One B-rep face of a CAD part: STEP entity #753.
In plain terms, the planar face has unit normal (1, 0, 0).
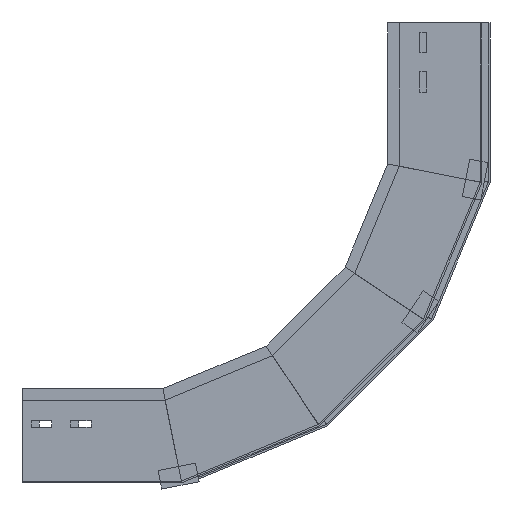
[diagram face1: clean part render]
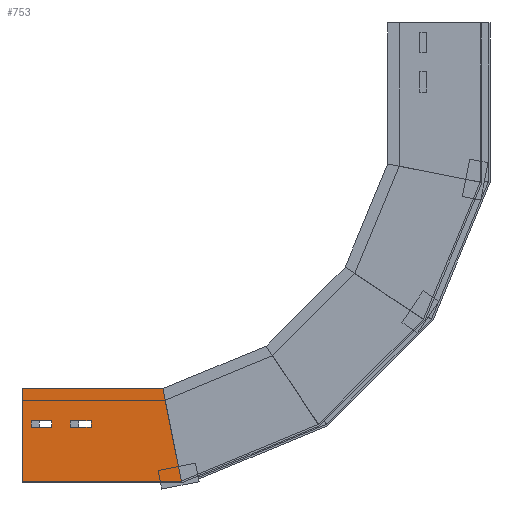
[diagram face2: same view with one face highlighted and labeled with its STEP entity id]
Its self-contained STEP definition (entity closure, numbers rounded to 3 decimals):
#6 = EDGE_LOOP ( 'NONE', ( #762, #1811, #141, #299 ) ) ;
#30 = EDGE_CURVE ( 'NONE', #997, #331, #841, .T. ) ;
#33 = ORIENTED_EDGE ( 'NONE', *, *, #143, .T. ) ;
#48 = LINE ( 'NONE', #607, #615 ) ;
#61 = LINE ( 'NONE', #1684, #849 ) ;
#67 = LINE ( 'NONE', #475, #1710 ) ;
#102 = ORIENTED_EDGE ( 'NONE', *, *, #1263, .T. ) ;
#112 = CARTESIAN_POINT ( 'NONE',  ( 0., 66., -73.505 ) ) ;
#126 = VECTOR ( 'NONE', #1705, 1000. ) ;
#138 = EDGE_LOOP ( 'NONE', ( #947, #1487, #102, #853 ) ) ;
#141 = ORIENTED_EDGE ( 'NONE', *, *, #1051, .T. ) ;
#143 = EDGE_CURVE ( 'NONE', #388, #1275, #904, .T. ) ;
#145 = CARTESIAN_POINT ( 'NONE',  ( 0., 100., 0. ) ) ;
#156 = VERTEX_POINT ( 'NONE', #768 ) ;
#172 = DIRECTION ( 'NONE',  ( 0., 1., 0. ) ) ;
#203 = EDGE_CURVE ( 'NONE', #1849, #1250, #673, .T. ) ;
#275 = FACE_BOUND ( 'NONE', #6, .T. ) ;
#290 = CARTESIAN_POINT ( 'NONE',  ( 0., 0., 0. ) ) ;
#298 = LINE ( 'NONE', #458, #333 ) ;
#299 = ORIENTED_EDGE ( 'NONE', *, *, #203, .T. ) ;
#312 = EDGE_CURVE ( 'NONE', #1637, #825, #48, .T. ) ;
#327 = CARTESIAN_POINT ( 'NONE',  ( 0., 59., -9.835 ) ) ;
#331 = VERTEX_POINT ( 'NONE', #828 ) ;
#333 = VECTOR ( 'NONE', #1773, 1000. ) ;
#344 = CARTESIAN_POINT ( 'NONE',  ( 0., 0., 0. ) ) ;
#382 = CARTESIAN_POINT ( 'NONE',  ( 0., 66., -31.835 ) ) ;
#388 = VERTEX_POINT ( 'NONE', #990 ) ;
#418 = EDGE_CURVE ( 'NONE', #1558, #985, #67, .T. ) ;
#425 = VECTOR ( 'NONE', #1557, 1000. ) ;
#450 = PLANE ( 'NONE',  #733 ) ;
#453 = DIRECTION ( 'NONE',  ( 0., 0., -1. ) ) ;
#458 = CARTESIAN_POINT ( 'NONE',  ( 0., 66., -9.835 ) ) ;
#467 = CARTESIAN_POINT ( 'NONE',  ( 0., 66., -51.505 ) ) ;
#475 = CARTESIAN_POINT ( 'NONE',  ( 0., 0., 0. ) ) ;
#557 = CARTESIAN_POINT ( 'NONE',  ( 0., 66., -31.835 ) ) ;
#590 = EDGE_LOOP ( 'NONE', ( #625, #1591, #864, #33 ) ) ;
#607 = CARTESIAN_POINT ( 'NONE',  ( 0., 66., -9.835 ) ) ;
#608 = EDGE_CURVE ( 'NONE', #825, #388, #1416, .T. ) ;
#609 = CARTESIAN_POINT ( 'NONE',  ( 0., 100., 0. ) ) ;
#612 = DIRECTION ( 'NONE',  ( 0., 0., -1. ) ) ;
#615 = VECTOR ( 'NONE', #453, 1000. ) ;
#625 = ORIENTED_EDGE ( 'NONE', *, *, #1156, .T. ) ;
#629 = LINE ( 'NONE', #1791, #1453 ) ;
#647 = DIRECTION ( 'NONE',  ( 0., 0., -1. ) ) ;
#651 = DIRECTION ( 'NONE',  ( 0., 1., 0. ) ) ;
#673 = LINE ( 'NONE', #1799, #1180 ) ;
#733 = AXIS2_PLACEMENT_3D ( 'NONE', #290, #854, #1869 ) ;
#753 = ADVANCED_FACE ( 'NONE', ( #275, #1876, #1459 ), #450, .F. ) ;
#754 = DIRECTION ( 'NONE',  ( 0., 0., -1. ) ) ;
#759 = VECTOR ( 'NONE', #754, 1000. ) ;
#762 = ORIENTED_EDGE ( 'NONE', *, *, #1502, .T. ) ;
#768 = CARTESIAN_POINT ( 'NONE',  ( 0., 66., -51.505 ) ) ;
#800 = CARTESIAN_POINT ( 'NONE',  ( 0., 66., -73.505 ) ) ;
#825 = VERTEX_POINT ( 'NONE', #557 ) ;
#828 = CARTESIAN_POINT ( 'NONE',  ( 0., 0., -169.6 ) ) ;
#841 = LINE ( 'NONE', #1286, #1485 ) ;
#849 = VECTOR ( 'NONE', #647, 1000. ) ;
#853 = ORIENTED_EDGE ( 'NONE', *, *, #30, .F. ) ;
#854 = DIRECTION ( 'NONE',  ( -1., 0., 0. ) ) ;
#864 = ORIENTED_EDGE ( 'NONE', *, *, #608, .T. ) ;
#904 = LINE ( 'NONE', #327, #1615 ) ;
#946 = CARTESIAN_POINT ( 'NONE',  ( 0., 59., -9.835 ) ) ;
#947 = ORIENTED_EDGE ( 'NONE', *, *, #1493, .F. ) ;
#985 = VERTEX_POINT ( 'NONE', #145 ) ;
#990 = CARTESIAN_POINT ( 'NONE',  ( 0., 59., -31.835 ) ) ;
#997 = VERTEX_POINT ( 'NONE', #1128 ) ;
#998 = VECTOR ( 'NONE', #172, 1000. ) ;
#1051 = EDGE_CURVE ( 'NONE', #1704, #1849, #1572, .T. ) ;
#1128 = CARTESIAN_POINT ( 'NONE',  ( 0., 100., -149.709 ) ) ;
#1156 = EDGE_CURVE ( 'NONE', #1275, #1637, #298, .T. ) ;
#1159 = DIRECTION ( 'NONE',  ( 0., 0., 1. ) ) ;
#1180 = VECTOR ( 'NONE', #1653, 1000. ) ;
#1237 = EDGE_CURVE ( 'NONE', #156, #1704, #629, .T. ) ;
#1250 = VERTEX_POINT ( 'NONE', #1359 ) ;
#1263 = EDGE_CURVE ( 'NONE', #1558, #331, #61, .T. ) ;
#1275 = VERTEX_POINT ( 'NONE', #946 ) ;
#1286 = CARTESIAN_POINT ( 'NONE',  ( 0., 32.452, -163.145 ) ) ;
#1359 = CARTESIAN_POINT ( 'NONE',  ( 0., 59., -51.505 ) ) ;
#1416 = LINE ( 'NONE', #382, #126 ) ;
#1453 = VECTOR ( 'NONE', #612, 1000. ) ;
#1459 = FACE_BOUND ( 'NONE', #590, .T. ) ;
#1465 = LINE ( 'NONE', #609, #759 ) ;
#1485 = VECTOR ( 'NONE', #1872, 1000. ) ;
#1487 = ORIENTED_EDGE ( 'NONE', *, *, #418, .F. ) ;
#1493 = EDGE_CURVE ( 'NONE', #985, #997, #1465, .T. ) ;
#1502 = EDGE_CURVE ( 'NONE', #1250, #156, #1769, .T. ) ;
#1557 = DIRECTION ( 'NONE',  ( 0., -1., 0. ) ) ;
#1558 = VERTEX_POINT ( 'NONE', #344 ) ;
#1572 = LINE ( 'NONE', #112, #425 ) ;
#1591 = ORIENTED_EDGE ( 'NONE', *, *, #312, .T. ) ;
#1615 = VECTOR ( 'NONE', #1159, 1000. ) ;
#1637 = VERTEX_POINT ( 'NONE', #1641 ) ;
#1641 = CARTESIAN_POINT ( 'NONE',  ( 0., 66., -9.835 ) ) ;
#1653 = DIRECTION ( 'NONE',  ( 0., 0., 1. ) ) ;
#1684 = CARTESIAN_POINT ( 'NONE',  ( 0., 0., 0. ) ) ;
#1704 = VERTEX_POINT ( 'NONE', #800 ) ;
#1705 = DIRECTION ( 'NONE',  ( 0., -1., 0. ) ) ;
#1710 = VECTOR ( 'NONE', #651, 1000. ) ;
#1754 = CARTESIAN_POINT ( 'NONE',  ( 0., 59., -73.505 ) ) ;
#1769 = LINE ( 'NONE', #467, #998 ) ;
#1773 = DIRECTION ( 'NONE',  ( 0., 1., 0. ) ) ;
#1791 = CARTESIAN_POINT ( 'NONE',  ( 0., 66., -51.505 ) ) ;
#1799 = CARTESIAN_POINT ( 'NONE',  ( 0., 59., -51.505 ) ) ;
#1811 = ORIENTED_EDGE ( 'NONE', *, *, #1237, .T. ) ;
#1849 = VERTEX_POINT ( 'NONE', #1754 ) ;
#1869 = DIRECTION ( 'NONE',  ( 0., 0., 1. ) ) ;
#1872 = DIRECTION ( 'NONE',  ( 0., -0.981, -0.195 ) ) ;
#1876 = FACE_OUTER_BOUND ( 'NONE', #138, .T. ) ;
